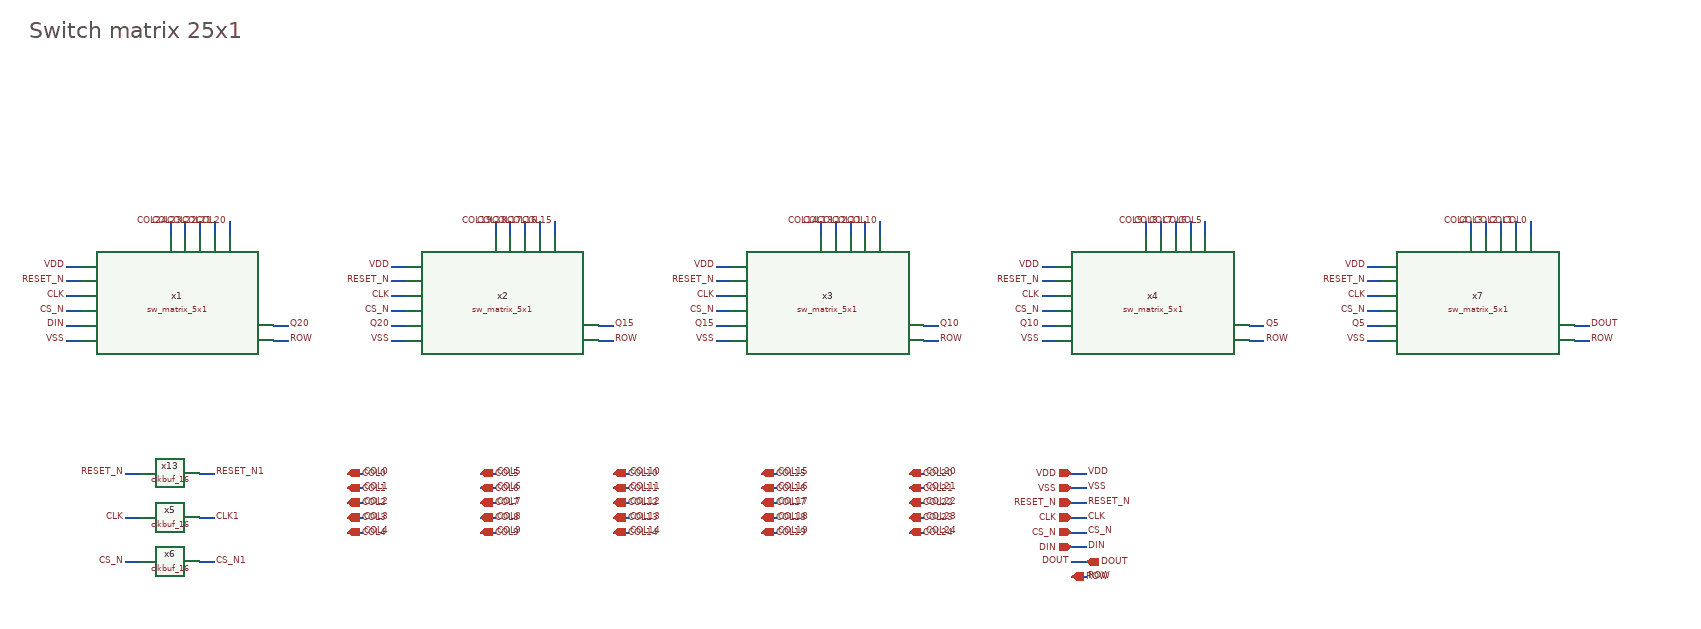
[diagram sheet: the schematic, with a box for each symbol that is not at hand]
v {xschem version=3.4.8RC file_version=1.3
* Copyright 2022 GlobalFoundries PDK Authors
*
* Licensed under the Apache License, Version 2.0 (the "License");
* you may not use this file except in compliance with the License.
* You may obtain a copy of the License at
*
*     https://www.apache.org/licenses/LICENSE-2.0
*
* Unless required by applicable law or agreed to in writing, software
* distributed under the License is distributed on an "AS IS" BASIS,
* WITHOUT WARRANTIES OR CONDITIONS OF ANY KIND, either express or implied.
* See the License for the specific language governing permissions and
* limitations under the License.

}
G {}
K {}
V {}
S {}
F {}
E {}
T {Switch matrix 25x1} 70 -850 0 0 1 1 {}
N 1480 -200 1500 -200 {lab=RESET_N}
N 1480 -180 1500 -180 {lab=CLK}
N 1480 -160 1500 -160 {lab=CS_N}
N 1480 -140 1500 -140 {lab=DIN}
N 500 -240 520 -240 {lab=COL0}
N 1480 -220 1500 -220 {lab=VSS}
N 1480 -240 1500 -240 {lab=VDD}
N 500 -220 520 -220 {lab=COL1}
N 500 -200 520 -200 {lab=COL2}
N 500 -180 520 -180 {lab=COL3}
N 500 -160 520 -160 {lab=COL4}
N 1480 -100 1500 -100 {lab=ROW}
N 1480 -120 1500 -120 {lab=DOUT}
N 120 -500 140 -500 {lab=RESET_N}
N 120 -480 140 -480 {lab=CLK}
N 120 -460 140 -460 {lab=CS_N}
N 120 -440 140 -440 {lab=DIN}
N 120 -420 140 -420 {lab=VSS}
N 120 -520 140 -520 {lab=VDD}
N 200 -180 220 -180 {lab=CLK}
N 300 -180 320 -180 {lab=CLK1}
N 200 -240 220 -240 {lab=RESET_N}
N 300 -240 320 -240 {lab=RESET_N1}
N 200 -120 220 -120 {lab=CS_N}
N 300 -120 320 -120 {lab=CS_N1}
N 400 -420 420 -420 {lab=ROW}
N 400 -440 420 -440 {lab=Q20}
N 680 -240 700 -240 {lab=COL5}
N 680 -220 700 -220 {lab=COL6}
N 680 -200 700 -200 {lab=COL7}
N 680 -180 700 -180 {lab=COL8}
N 680 -160 700 -160 {lab=COL9}
N 860 -240 880 -240 {lab=COL10}
N 860 -220 880 -220 {lab=COL11}
N 860 -200 880 -200 {lab=COL12}
N 860 -180 880 -180 {lab=COL13}
N 860 -160 880 -160 {lab=COL14}
N 1060 -240 1080 -240 {lab=COL15}
N 1060 -220 1080 -220 {lab=COL16}
N 1060 -200 1080 -200 {lab=COL17}
N 1060 -180 1080 -180 {lab=COL18}
N 1060 -160 1080 -160 {lab=COL19}
N 1260 -240 1280 -240 {lab=COL20}
N 1260 -220 1280 -220 {lab=COL21}
N 1260 -200 1280 -200 {lab=COL22}
N 1260 -180 1280 -180 {lab=COL23}
N 1260 -160 1280 -160 {lab=COL24}
N 340 -580 340 -560 {lab=COL20}
N 320 -580 320 -560 {lab=COL21}
N 300 -580 300 -560 {lab=COL22}
N 280 -580 280 -560 {lab=COL23}
N 260 -580 260 -560 {lab=COL24}
N 560 -500 580 -500 {lab=RESET_N}
N 560 -480 580 -480 {lab=CLK}
N 560 -460 580 -460 {lab=CS_N}
N 560 -440 580 -440 {lab=Q20}
N 560 -420 580 -420 {lab=VSS}
N 560 -520 580 -520 {lab=VDD}
N 840 -420 860 -420 {lab=ROW}
N 840 -440 860 -440 {lab=Q15}
N 780 -580 780 -560 {lab=COL15}
N 760 -580 760 -560 {lab=COL16}
N 740 -580 740 -560 {lab=COL17}
N 720 -580 720 -560 {lab=COL18}
N 700 -580 700 -560 {lab=COL19}
N 1000 -500 1020 -500 {lab=RESET_N}
N 1000 -480 1020 -480 {lab=CLK}
N 1000 -460 1020 -460 {lab=CS_N}
N 1000 -440 1020 -440 {lab=Q15}
N 1000 -420 1020 -420 {lab=VSS}
N 1000 -520 1020 -520 {lab=VDD}
N 1280 -420 1300 -420 {lab=ROW}
N 1280 -440 1300 -440 {lab=Q10}
N 1220 -580 1220 -560 {lab=COL10}
N 1200 -580 1200 -560 {lab=COL11}
N 1180 -580 1180 -560 {lab=COL12}
N 1160 -580 1160 -560 {lab=COL13}
N 1140 -580 1140 -560 {lab=COL14}
N 1440 -500 1460 -500 {lab=RESET_N}
N 1440 -480 1460 -480 {lab=CLK}
N 1440 -460 1460 -460 {lab=CS_N}
N 1440 -440 1460 -440 {lab=Q10}
N 1440 -420 1460 -420 {lab=VSS}
N 1440 -520 1460 -520 {lab=VDD}
N 1720 -420 1740 -420 {lab=ROW}
N 1720 -440 1740 -440 {lab=Q5}
N 1660 -580 1660 -560 {lab=COL5}
N 1640 -580 1640 -560 {lab=COL6}
N 1620 -580 1620 -560 {lab=COL7}
N 1600 -580 1600 -560 {lab=COL8}
N 1580 -580 1580 -560 {lab=COL9}
N 1880 -500 1900 -500 {lab=RESET_N}
N 1880 -480 1900 -480 {lab=CLK}
N 1880 -460 1900 -460 {lab=CS_N}
N 1880 -440 1900 -440 {lab=Q5}
N 1880 -420 1900 -420 {lab=GND}
N 1880 -520 1900 -520 {lab=VDD}
N 2160 -420 2180 -420 {lab=ROW}
N 2160 -440 2180 -440 {lab=DOUT}
N 2100 -580 2100 -560 {lab=COL0}
N 2080 -580 2080 -560 {lab=COL1}
N 2060 -580 2060 -560 {lab=COL2}
N 2040 -580 2040 -560 {lab=COL3}
N 2020 -580 2020 -560 {lab=COL4}
C {devices/title.sym} 160 -30 0 0 {name=l5 author="Yutaka KOTANI"}
C {lab_pin.sym} 1500 -200 0 1 {name=p80 sig_type=std_logic lab=RESET_N}
C {lab_pin.sym} 1500 -160 0 1 {name=p81 sig_type=std_logic lab=CS_N}
C {lab_pin.sym} 1500 -140 0 1 {name=p82 sig_type=std_logic lab=DIN}
C {lab_pin.sym} 520 -240 0 1 {name=p83 sig_type=std_logic lab=COL0}
C {lab_pin.sym} 1500 -180 0 1 {name=p84 sig_type=std_logic lab=CLK}
C {lab_pin.sym} 1500 -220 0 1 {name=p85 sig_type=std_logic lab=VSS}
C {lab_pin.sym} 1500 -240 0 1 {name=p86 sig_type=std_logic lab=VDD}
C {ipin.sym} 1480 -240 0 0 {name=p87 lab=VDD}
C {ipin.sym} 1480 -220 0 0 {name=p88 lab=VSS}
C {ipin.sym} 1480 -200 0 0 {name=p89 lab=RESET_N}
C {ipin.sym} 1480 -180 0 0 {name=p90 lab=CLK}
C {ipin.sym} 1480 -160 0 0 {name=p91 lab=CS_N}
C {ipin.sym} 1480 -140 0 0 {name=p92 lab=DIN}
C {iopin.sym} 500 -240 0 1 {name=p93 lab=COL0}
C {lab_pin.sym} 520 -220 0 1 {name=p94 sig_type=std_logic lab=COL1}
C {iopin.sym} 500 -220 0 1 {name=p95 lab=COL1}
C {lab_pin.sym} 520 -200 0 1 {name=p96 sig_type=std_logic lab=COL2}
C {iopin.sym} 500 -200 0 1 {name=p97 lab=COL2}
C {lab_pin.sym} 520 -180 0 1 {name=p98 sig_type=std_logic lab=COL3}
C {iopin.sym} 500 -180 0 1 {name=p99 lab=COL3}
C {lab_pin.sym} 520 -160 0 1 {name=p100 sig_type=std_logic lab=COL4}
C {iopin.sym} 500 -160 0 1 {name=p101 lab=COL4}
C {lab_pin.sym} 1500 -100 0 1 {name=p102 sig_type=std_logic lab=ROW}
C {iopin.sym} 1480 -100 0 1 {name=p103 lab=ROW}
C {lab_pin.sym} 1480 -120 0 0 {name=p2 sig_type=std_logic lab=DOUT}
C {opin.sym} 1500 -120 0 0 {name=p3 lab=DOUT}
C {libs/core_analog/sw_matrix/sw_matrix_5x1.sym} 280 -460 0 0 {name=x1}
C {lab_pin.sym} 120 -500 0 0 {name=p4 sig_type=std_logic lab=RESET_N}
C {lab_pin.sym} 120 -460 0 0 {name=p5 sig_type=std_logic lab=CS_N}
C {lab_pin.sym} 120 -440 0 0 {name=p6 sig_type=std_logic lab=DIN}
C {lab_pin.sym} 120 -480 0 0 {name=p7 sig_type=std_logic lab=CLK}
C {lab_pin.sym} 120 -420 0 0 {name=p8 sig_type=std_logic lab=VSS}
C {lab_pin.sym} 120 -520 0 0 {name=p9 sig_type=std_logic lab=VDD}
C {lab_pin.sym} 200 -180 0 0 {name=p10 sig_type=std_logic lab=CLK}
C {lab_pin.sym} 320 -180 0 1 {name=p11 sig_type=std_logic lab=CLK1}
C {libs/gf180mcu_stdcells/clkbuf_16.sym} 260 -180 0 0 {name=x5 VGND=VSS VNB=VDD VPB=VSS VPWR=VDD prefix=gf180mcu_fd_sc_mcu7t5v0__ }
C {lab_pin.sym} 200 -240 0 0 {name=p12 sig_type=std_logic lab=RESET_N}
C {lab_pin.sym} 320 -240 0 1 {name=p13 sig_type=std_logic lab=RESET_N1}
C {libs/gf180mcu_stdcells/clkbuf_16.sym} 260 -240 0 0 {name=x13 VGND=VSS VNB=VDD VPB=VSS VPWR=VDD prefix=gf180mcu_fd_sc_mcu7t5v0__ }
C {lab_pin.sym} 200 -120 0 0 {name=p14 sig_type=std_logic lab=CS_N}
C {lab_pin.sym} 320 -120 0 1 {name=p16 sig_type=std_logic lab=CS_N1}
C {libs/gf180mcu_stdcells/clkbuf_16.sym} 260 -120 0 0 {name=x6 VGND=VSS VNB=VDD VPB=VSS VPWR=VDD prefix=gf180mcu_fd_sc_mcu7t5v0__ }
C {lab_pin.sym} 420 -420 0 1 {name=p1 sig_type=std_logic lab=ROW}
C {lab_pin.sym} 420 -440 0 1 {name=p15 sig_type=std_logic lab=Q20}
C {lab_pin.sym} 700 -240 0 1 {name=p17 sig_type=std_logic lab=COL5}
C {iopin.sym} 680 -240 0 1 {name=p18 lab=COL5}
C {lab_pin.sym} 700 -220 0 1 {name=p19 sig_type=std_logic lab=COL6}
C {iopin.sym} 680 -220 0 1 {name=p20 lab=COL6}
C {lab_pin.sym} 700 -200 0 1 {name=p21 sig_type=std_logic lab=COL7}
C {iopin.sym} 680 -200 0 1 {name=p22 lab=COL7}
C {lab_pin.sym} 700 -180 0 1 {name=p23 sig_type=std_logic lab=COL8}
C {iopin.sym} 680 -180 0 1 {name=p24 lab=COL8}
C {lab_pin.sym} 700 -160 0 1 {name=p25 sig_type=std_logic lab=COL9}
C {iopin.sym} 680 -160 0 1 {name=p26 lab=COL9}
C {lab_pin.sym} 880 -240 0 1 {name=p27 sig_type=std_logic lab=COL10}
C {iopin.sym} 860 -240 0 1 {name=p28 lab=COL10}
C {lab_pin.sym} 880 -220 0 1 {name=p29 sig_type=std_logic lab=COL11}
C {iopin.sym} 860 -220 0 1 {name=p30 lab=COL11}
C {lab_pin.sym} 880 -200 0 1 {name=p31 sig_type=std_logic lab=COL12}
C {iopin.sym} 860 -200 0 1 {name=p32 lab=COL12}
C {lab_pin.sym} 880 -180 0 1 {name=p33 sig_type=std_logic lab=COL13}
C {iopin.sym} 860 -180 0 1 {name=p34 lab=COL13}
C {lab_pin.sym} 880 -160 0 1 {name=p35 sig_type=std_logic lab=COL14}
C {iopin.sym} 860 -160 0 1 {name=p36 lab=COL14}
C {lab_pin.sym} 1080 -240 0 1 {name=p37 sig_type=std_logic lab=COL15}
C {iopin.sym} 1060 -240 0 1 {name=p38 lab=COL15}
C {lab_pin.sym} 1080 -220 0 1 {name=p39 sig_type=std_logic lab=COL16}
C {iopin.sym} 1060 -220 0 1 {name=p40 lab=COL16}
C {lab_pin.sym} 1080 -200 0 1 {name=p41 sig_type=std_logic lab=COL17}
C {iopin.sym} 1060 -200 0 1 {name=p42 lab=COL17}
C {lab_pin.sym} 1080 -180 0 1 {name=p43 sig_type=std_logic lab=COL18}
C {iopin.sym} 1060 -180 0 1 {name=p44 lab=COL18}
C {lab_pin.sym} 1080 -160 0 1 {name=p45 sig_type=std_logic lab=COL19}
C {iopin.sym} 1060 -160 0 1 {name=p46 lab=COL19}
C {lab_pin.sym} 1280 -240 0 1 {name=p47 sig_type=std_logic lab=COL20}
C {iopin.sym} 1260 -240 0 1 {name=p48 lab=COL20}
C {lab_pin.sym} 1280 -220 0 1 {name=p49 sig_type=std_logic lab=COL21}
C {iopin.sym} 1260 -220 0 1 {name=p50 lab=COL21}
C {lab_pin.sym} 1280 -200 0 1 {name=p51 sig_type=std_logic lab=COL22}
C {iopin.sym} 1260 -200 0 1 {name=p52 lab=COL22}
C {lab_pin.sym} 1280 -180 0 1 {name=p53 sig_type=std_logic lab=COL23}
C {iopin.sym} 1260 -180 0 1 {name=p54 lab=COL23}
C {lab_pin.sym} 1280 -160 0 1 {name=p55 sig_type=std_logic lab=COL24}
C {iopin.sym} 1260 -160 0 1 {name=p56 lab=COL24}
C {lab_pin.sym} 340 -580 3 1 {name=p57 sig_type=std_logic lab=COL20}
C {lab_pin.sym} 320 -580 3 1 {name=p58 sig_type=std_logic lab=COL21}
C {lab_pin.sym} 300 -580 3 1 {name=p59 sig_type=std_logic lab=COL22}
C {lab_pin.sym} 280 -580 3 1 {name=p60 sig_type=std_logic lab=COL23}
C {lab_pin.sym} 260 -580 3 1 {name=p61 sig_type=std_logic lab=COL24}
C {libs/core_analog/sw_matrix/sw_matrix_5x1.sym} 720 -460 0 0 {name=x2}
C {lab_pin.sym} 560 -500 0 0 {name=p62 sig_type=std_logic lab=RESET_N}
C {lab_pin.sym} 560 -460 0 0 {name=p63 sig_type=std_logic lab=CS_N}
C {lab_pin.sym} 560 -440 0 0 {name=p64 sig_type=std_logic lab=Q20}
C {lab_pin.sym} 560 -480 0 0 {name=p65 sig_type=std_logic lab=CLK}
C {lab_pin.sym} 560 -420 0 0 {name=p66 sig_type=std_logic lab=VSS}
C {lab_pin.sym} 560 -520 0 0 {name=p67 sig_type=std_logic lab=VDD}
C {lab_pin.sym} 860 -420 0 1 {name=p68 sig_type=std_logic lab=ROW}
C {lab_pin.sym} 860 -440 0 1 {name=p69 sig_type=std_logic lab=Q15}
C {lab_pin.sym} 780 -580 3 1 {name=p70 sig_type=std_logic lab=COL15}
C {lab_pin.sym} 760 -580 3 1 {name=p71 sig_type=std_logic lab=COL16}
C {lab_pin.sym} 740 -580 3 1 {name=p72 sig_type=std_logic lab=COL17}
C {lab_pin.sym} 720 -580 3 1 {name=p73 sig_type=std_logic lab=COL18}
C {lab_pin.sym} 700 -580 3 1 {name=p74 sig_type=std_logic lab=COL19}
C {libs/core_analog/sw_matrix/sw_matrix_5x1.sym} 1160 -460 0 0 {name=x3}
C {lab_pin.sym} 1000 -500 0 0 {name=p75 sig_type=std_logic lab=RESET_N}
C {lab_pin.sym} 1000 -460 0 0 {name=p76 sig_type=std_logic lab=CS_N}
C {lab_pin.sym} 1000 -440 0 0 {name=p77 sig_type=std_logic lab=Q15}
C {lab_pin.sym} 1000 -480 0 0 {name=p78 sig_type=std_logic lab=CLK}
C {lab_pin.sym} 1000 -420 0 0 {name=p79 sig_type=std_logic lab=VSS}
C {lab_pin.sym} 1000 -520 0 0 {name=p104 sig_type=std_logic lab=VDD}
C {lab_pin.sym} 1300 -420 0 1 {name=p105 sig_type=std_logic lab=ROW}
C {lab_pin.sym} 1300 -440 0 1 {name=p106 sig_type=std_logic lab=Q10}
C {lab_pin.sym} 1220 -580 3 1 {name=p107 sig_type=std_logic lab=COL10}
C {lab_pin.sym} 1200 -580 3 1 {name=p108 sig_type=std_logic lab=COL11}
C {lab_pin.sym} 1180 -580 3 1 {name=p109 sig_type=std_logic lab=COL12}
C {lab_pin.sym} 1160 -580 3 1 {name=p110 sig_type=std_logic lab=COL13}
C {lab_pin.sym} 1140 -580 3 1 {name=p111 sig_type=std_logic lab=COL14}
C {libs/core_analog/sw_matrix/sw_matrix_5x1.sym} 1600 -460 0 0 {name=x4}
C {lab_pin.sym} 1440 -500 0 0 {name=p112 sig_type=std_logic lab=RESET_N}
C {lab_pin.sym} 1440 -460 0 0 {name=p113 sig_type=std_logic lab=CS_N}
C {lab_pin.sym} 1440 -440 0 0 {name=p114 sig_type=std_logic lab=Q10}
C {lab_pin.sym} 1440 -480 0 0 {name=p115 sig_type=std_logic lab=CLK}
C {lab_pin.sym} 1440 -420 0 0 {name=p116 sig_type=std_logic lab=VSS}
C {lab_pin.sym} 1440 -520 0 0 {name=p117 sig_type=std_logic lab=VDD}
C {lab_pin.sym} 1740 -420 0 1 {name=p118 sig_type=std_logic lab=ROW}
C {lab_pin.sym} 1740 -440 0 1 {name=p119 sig_type=std_logic lab=Q5}
C {lab_pin.sym} 1660 -580 3 1 {name=p120 sig_type=std_logic lab=COL5}
C {lab_pin.sym} 1640 -580 3 1 {name=p121 sig_type=std_logic lab=COL6}
C {lab_pin.sym} 1620 -580 3 1 {name=p122 sig_type=std_logic lab=COL7}
C {lab_pin.sym} 1600 -580 3 1 {name=p123 sig_type=std_logic lab=COL8}
C {lab_pin.sym} 1580 -580 3 1 {name=p124 sig_type=std_logic lab=COL9}
C {libs/core_analog/sw_matrix/sw_matrix_5x1.sym} 2040 -460 0 0 {name=x7}
C {lab_pin.sym} 1880 -500 0 0 {name=p125 sig_type=std_logic lab=RESET_N}
C {lab_pin.sym} 1880 -460 0 0 {name=p126 sig_type=std_logic lab=CS_N}
C {lab_pin.sym} 1880 -440 0 0 {name=p127 sig_type=std_logic lab=Q5}
C {lab_pin.sym} 1880 -480 0 0 {name=p128 sig_type=std_logic lab=CLK}
C {lab_pin.sym} 1880 -420 0 0 {name=p129 sig_type=std_logic lab=VSS}
C {lab_pin.sym} 1880 -520 0 0 {name=p130 sig_type=std_logic lab=VDD}
C {lab_pin.sym} 2180 -420 0 1 {name=p131 sig_type=std_logic lab=ROW}
C {lab_pin.sym} 2180 -440 0 1 {name=p132 sig_type=std_logic lab=DOUT}
C {lab_pin.sym} 2100 -580 3 1 {name=p133 sig_type=std_logic lab=COL0}
C {lab_pin.sym} 2080 -580 3 1 {name=p134 sig_type=std_logic lab=COL1}
C {lab_pin.sym} 2060 -580 3 1 {name=p135 sig_type=std_logic lab=COL2}
C {lab_pin.sym} 2040 -580 3 1 {name=p136 sig_type=std_logic lab=COL3}
C {lab_pin.sym} 2020 -580 3 1 {name=p137 sig_type=std_logic lab=COL4}
